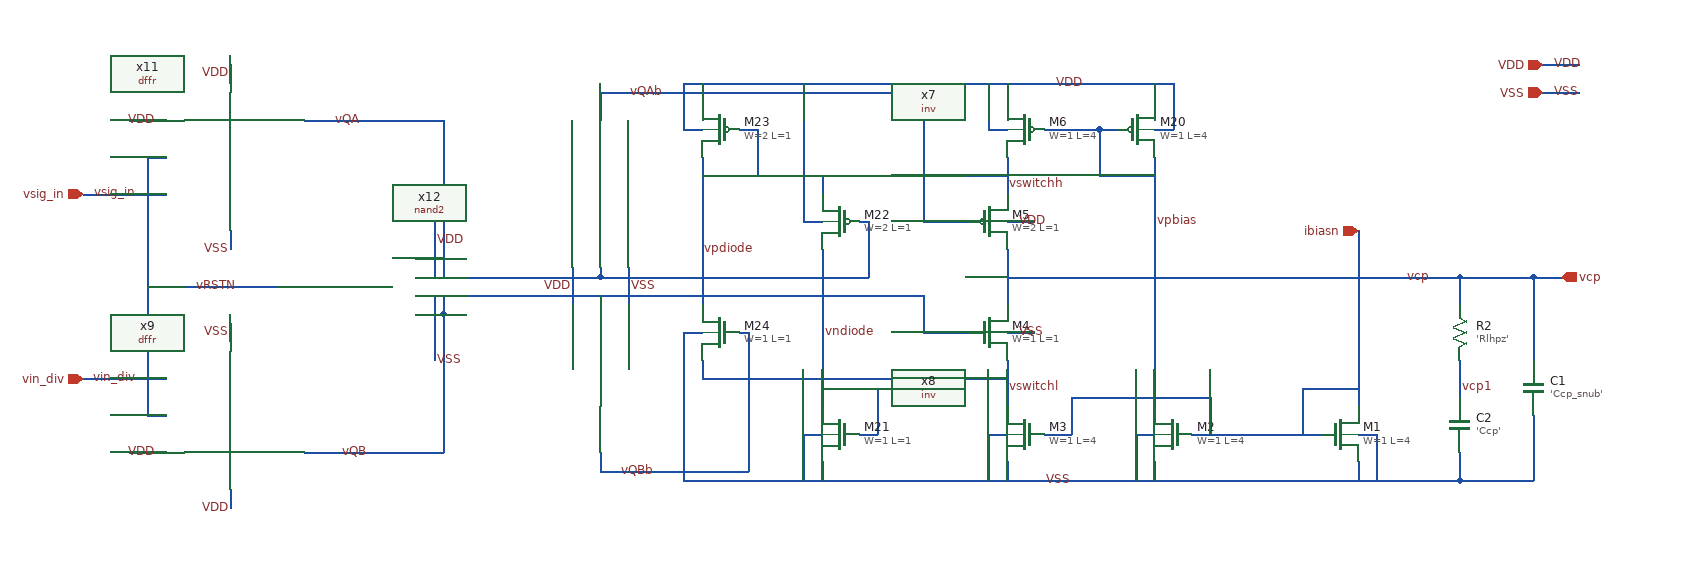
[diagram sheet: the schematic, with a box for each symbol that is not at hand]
v {xschem version=2.9.9 file_version=1.2 }
G {}
K {}
V {}
S {}
E {}
N 160 -260 250 -260 { lab=vin_div}
N 160 -460 250 -460 { lab=vsig_in}
N 1320 -170 1320 -150 { lab=VSS}
N 1300 -200 1320 -200 { lab=VSS}
N 1300 -200 1300 -150 { lab=VSS}
N 1320 -530 1340 -530 { lab=VDD}
N 1320 -580 1320 -560 { lab=VDD}
N 1340 -580 1340 -530 { lab=VDD}
N 1360 -200 1430 -200 { lab=ibiasn}
N 1260 -530 1260 -480 { lab=vpbias}
N 1260 -480 1320 -480 { lab=vpbias}
N 1260 -530 1280 -530 { lab=vpbias}
N 1320 -500 1320 -230 { lab=vpbias}
N 1540 -170 1540 -150 { lab=VSS}
N 1540 -200 1560 -200 { lab=VSS}
N 1560 -200 1560 -150 { lab=VSS}
N 1200 -530 1260 -530 { lab=vpbias}
N 1140 -530 1160 -530 { lab=VDD}
N 1140 -580 1140 -530 { lab=VDD}
N 1160 -580 1160 -560 { lab=VDD}
N 1160 -170 1160 -150 { lab=VSS}
N 1140 -200 1160 -200 { lab=VSS}
N 1140 -200 1140 -150 { lab=VSS}
N 1380 -240 1380 -200 { lab=ibiasn}
N 1230 -240 1380 -240 { lab=ibiasn}
N 1230 -240 1230 -200 { lab=ibiasn}
N 1200 -200 1230 -200 { lab=ibiasn}
N 1160 -500 1160 -460 { lab=vswitchh}
N 1160 -400 1160 -340 { lab=vcp}
N 1160 -280 1160 -230 { lab=vswitchl}
N 1160 -310 1190 -310 { lab=VSS}
N 1160 -430 1190 -430 { lab=VDD}
N 1540 -420 1540 -230 { lab=ibiasn}
N 1480 -250 1540 -250 { lab=ibiasn}
N 1160 -370 1580 -370 { lab=vcp}
N 940 -430 960 -430 { lab=VDD}
N 1000 -200 1020 -200 { lab=vndiode}
N 1020 -250 1020 -200 { lab=vndiode}
N 960 -250 1020 -250 { lab=vndiode}
N 830 -280 830 -260 { lab=vswitchl}
N 810 -310 830 -310 { lab=VSS}
N 810 -530 830 -530 { lab=VDD}
N 810 -580 810 -530 { lab=VDD}
N 830 -580 830 -560 { lab=VDD}
N 940 -200 960 -200 { lab=VSS}
N 960 -170 960 -150 { lab=VSS}
N 940 -200 940 -150 { lab=VSS}
N 870 -530 890 -530 { lab=vpdiode}
N 890 -530 890 -480 { lab=vpdiode}
N 830 -480 890 -480 { lab=vpdiode}
N 960 -480 1160 -480 { lab=vswitchh}
N 830 -260 1160 -260 { lab=vswitchl}
N 1100 -430 1120 -430 { lab=vQAb}
N 1000 -430 1010 -430 { lab=vQA}
N 1100 -310 1120 -310 { lab=vQB}
N 870 -310 880 -310 { lab=vQBb}
N 1070 -430 1100 -430 { lab=vQAb}
N 1070 -350 1070 -310 { lab=vQB}
N 1070 -310 1100 -310 { lab=vQB}
N 960 -480 960 -460 { lab=vswitchh}
N 960 -400 960 -230 { lab=vndiode}
N 940 -580 940 -430 { lab=VDD}
N 810 -310 810 -150 { lab=VSS}
N 830 -500 830 -340 { lab=vpdiode}
N 400 -540 550 -540 { lab=vQA}
N 400 -180 550 -180 { lab=vQB}
N 230 -360 370 -360 { lab=vRSTN}
N 720 -570 720 -540 { lab=vQAb}
N 720 -180 720 -160 { lab=vQBb}
N 720 -380 720 -370 { lab=vQA}
N 720 -350 720 -340 { lab=vQB}
N 550 -540 550 -370 { lab=vQA}
N 550 -370 720 -370 { lab=vQA}
N 720 -570 1070 -570 { lab=vQAb}
N 1070 -570 1070 -430 { lab=vQAb}
N 720 -370 1010 -370 { lab=vQA}
N 1010 -430 1010 -370 { lab=vQA}
N 550 -350 550 -330 { lab=vQB}
N 550 -350 1070 -350 { lab=vQB}
N 720 -160 880 -160 { lab=vQBb}
N 880 -310 880 -160 { lab=vQBb}
N 230 -220 250 -220 { lab=vRSTN}
N 230 -500 230 -220 { lab=vRSTN}
N 230 -500 250 -500 { lab=vRSTN}
N 210 -540 250 -540 { lab=VDD}
N 210 -180 250 -180 { lab=VDD}
N 550 -330 550 -180 { lab=vQB}
N 1430 -200 1500 -200 { lab=ibiasn}
N 1480 -250 1480 -200 { lab=ibiasn}
N 1650 -370 1650 -340 { lab=vcp}
N 1650 -180 1650 -150 { lab=VSS}
N 1650 -280 1650 -240 { lab=vcp1}
N 1580 -370 1650 -370 { lab=vcp}
N 810 -150 1650 -150 { lab=VSS}
N 1650 -370 1730 -370 { lab=vcp}
N 1730 -370 1730 -280 { lab=vcp}
N 1730 -220 1730 -150 { lab=VSS}
N 1650 -150 1730 -150 { lab=VSS}
N 1740 -570 1780 -570 { lab=VSS}
N 1740 -600 1780 -600 { lab=VDD}
N 1730 -370 1760 -370 { lab=vcp}
N 810 -580 1340 -580 { lab=VDD}
N 690 -380 690 -340 { lab=VDD}
N 750 -380 750 -340 { lab=VSS}
N 320 -420 320 -400 { lab=VSS}
N 320 -600 320 -580 { lab=VDD}
N 320 -320 320 -300 { lab=VSS}
N 320 -140 320 -120 { lab=VDD}
N 540 -310 540 -280 { lab=#net1}
N 540 -430 540 -400 { lab=VDD}
N 520 -390 550 -390 {}
N 520 -330 550 -330 {}
N 520 -370 540 -370 {}
N 540 -400 540 -370 {}
N 540 -350 540 -310 {}
N 520 -350 540 -350 {}
C {devices/title.sym} 160 -30 0 0 {name=l1 author="Nikhil Poole"}
C {devices/lab_wire.sym} 220 -460 0 0 {name=l2 sig_type=std_logic lab=vsig_in}
C {devices/lab_wire.sym} 220 -260 0 0 {name=l3 sig_type=std_logic lab=vin_div}
C {devices/lab_wire.sym} 1320 -430 0 1 {name=l6 sig_type=std_logic lab=vpbias}
C {sky130_fd_pr/nfet_01v8.sym} 1520 -200 0 0 {name=M1
L=4
W=1
nf=1 
mult=10
ad="'int((nf+1)/2) * W/nf * 0.29'" 
pd="'2*int((nf+1)/2) * (W/nf + 0.29)'"
as="'int((nf+2)/2) * W/nf * 0.29'" 
ps="'2*int((nf+2)/2) * (W/nf + 0.29)'"
nrd="'0.29 / W'" nrs="'0.29 / W'"
sa=0 sb=0 sd=0
model=nfet_01v8
spiceprefix=X
}
C {sky130_fd_pr/nfet_01v8.sym} 1340 -200 0 1 {name=M2
L=4
W=1
nf=1 
mult=1
ad="'int((nf+1)/2) * W/nf * 0.29'" 
pd="'2*int((nf+1)/2) * (W/nf + 0.29)'"
as="'int((nf+2)/2) * W/nf * 0.29'" 
ps="'2*int((nf+2)/2) * (W/nf + 0.29)'"
nrd="'0.29 / W'" nrs="'0.29 / W'"
sa=0 sb=0 sd=0
model=nfet_01v8
spiceprefix=X
}
C {sky130_fd_pr/nfet_01v8.sym} 1180 -200 0 1 {name=M3
L=4
W=1
nf=1 
mult=1
ad="'int((nf+1)/2) * W/nf * 0.29'" 
pd="'2*int((nf+1)/2) * (W/nf + 0.29)'"
as="'int((nf+2)/2) * W/nf * 0.29'" 
ps="'2*int((nf+2)/2) * (W/nf + 0.29)'"
nrd="'0.29 / W'" nrs="'0.29 / W'"
sa=0 sb=0 sd=0
model=nfet_01v8
spiceprefix=X
}
C {sky130_fd_pr/nfet_01v8_lvt.sym} 1140 -310 0 0 {name=M4
L=1
W=1
nf=1
mult=1
ad="'int((nf+1)/2) * W/nf * 0.29'" 
pd="'2*int((nf+1)/2) * (W/nf + 0.29)'"
as="'int((nf+2)/2) * W/nf * 0.29'" 
ps="'2*int((nf+2)/2) * (W/nf + 0.29)'"
nrd="'0.29 / W'" nrs="'0.29 / W'"
sa=0 sb=0 sd=0
model=nfet_01v8_lvt
spiceprefix=X
}
C {sky130_fd_pr/pfet_01v8_lvt.sym} 1140 -430 0 0 {name=M5
L=1
W=2
nf=1
mult=1
ad="'int((nf+1)/2) * W/nf * 0.29'" 
pd="'2*int((nf+1)/2) * (W/nf + 0.29)'"
as="'int((nf+2)/2) * W/nf * 0.29'" 
ps="'2*int((nf+2)/2) * (W/nf + 0.29)'"
nrd="'0.29 / W'" nrs="'0.29 / W'"
sa=0 sb=0 sd=0
model=pfet_01v8_lvt
spiceprefix=X
}
C {sky130_fd_pr/pfet_01v8.sym} 1180 -530 0 1 {name=M6
L=4
W=1
nf=1
mult=8
ad="'int((nf+1)/2) * W/nf * 0.29'" 
pd="'2*int((nf+1)/2) * (W/nf + 0.29)'"
as="'int((nf+2)/2) * W/nf * 0.29'" 
ps="'2*int((nf+2)/2) * (W/nf + 0.29)'"
nrd="'0.29 / W'" nrs="'0.29 / W'"
sa=0 sb=0 sd=0
model=pfet_01v8
spiceprefix=X
}
C {sky130_fd_pr/pfet_01v8.sym} 1300 -530 0 0 {name=M20
L=4
W=1
nf=1
mult=8
ad="'int((nf+1)/2) * W/nf * 0.29'" 
pd="'2*int((nf+1)/2) * (W/nf + 0.29)'"
as="'int((nf+2)/2) * W/nf * 0.29'" 
ps="'2*int((nf+2)/2) * (W/nf + 0.29)'"
nrd="'0.29 / W'" nrs="'0.29 / W'"
sa=0 sb=0 sd=0
model=pfet_01v8
spiceprefix=X
}
C {devices/capa.sym} 1650 -210 0 0 {name=C2
m=1
value='Ccp'
footprint=1206
device="ceramic capacitor"}
C {devices/lab_wire.sym} 470 -180 0 0 {name=l37 sig_type=std_logic lab=vQB}
C {devices/lab_wire.sym} 1160 -470 0 1 {name=l38 sig_type=std_logic lab=vswitchh}
C {devices/lab_wire.sym} 1160 -250 0 1 {name=l39 sig_type=std_logic lab=vswitchl}
C {sky130_fd_pr/nfet_01v8.sym} 980 -200 0 1 {name=M21
L=1
W=1
nf=1 
mult=1
ad="'int((nf+1)/2) * W/nf * 0.29'" 
pd="'2*int((nf+1)/2) * (W/nf + 0.29)'"
as="'int((nf+2)/2) * W/nf * 0.29'" 
ps="'2*int((nf+2)/2) * (W/nf + 0.29)'"
nrd="'0.29 / W'" nrs="'0.29 / W'"
sa=0 sb=0 sd=0
model=nfet_01v8
spiceprefix=X
}
C {sky130_fd_pr/pfet_01v8.sym} 980 -430 0 1 {name=M22
L=1
W=2
nf=1
mult=1
ad="'int((nf+1)/2) * W/nf * 0.29'" 
pd="'2*int((nf+1)/2) * (W/nf + 0.29)'"
as="'int((nf+2)/2) * W/nf * 0.29'" 
ps="'2*int((nf+2)/2) * (W/nf + 0.29)'"
nrd="'0.29 / W'" nrs="'0.29 / W'"
sa=0 sb=0 sd=0
model=pfet_01v8
spiceprefix=X
}
C {devices/lab_wire.sym} 430 -540 0 1 {name=l40 sig_type=std_logic lab=vQA}
C {sky130_fd_pr/pfet_01v8.sym} 850 -530 0 1 {name=M23
L=1
W=2
nf=1
mult=1
ad="'int((nf+1)/2) * W/nf * 0.29'" 
pd="'2*int((nf+1)/2) * (W/nf + 0.29)'"
as="'int((nf+2)/2) * W/nf * 0.29'" 
ps="'2*int((nf+2)/2) * (W/nf + 0.29)'"
nrd="'0.29 / W'" nrs="'0.29 / W'"
sa=0 sb=0 sd=0
model=pfet_01v8
spiceprefix=X
}
C {sky130_fd_pr/nfet_01v8.sym} 850 -310 0 1 {name=M24
L=1
W=1
nf=1 
mult=1
ad="'int((nf+1)/2) * W/nf * 0.29'" 
pd="'2*int((nf+1)/2) * (W/nf + 0.29)'"
as="'int((nf+2)/2) * W/nf * 0.29'" 
ps="'2*int((nf+2)/2) * (W/nf + 0.29)'"
nrd="'0.29 / W'" nrs="'0.29 / W'"
sa=0 sb=0 sd=0
model=nfet_01v8
spiceprefix=X
}
C {devices/lab_wire.sym} 780 -160 0 0 {name=l41 sig_type=std_logic lab=vQBb}
C {devices/lab_wire.sym} 1590 -370 0 1 {name=l44 sig_type=std_logic lab=vcp}
C {devices/lab_wire.sym} 280 -360 0 1 {name=l49 sig_type=std_logic lab=vRSTN}
C {/home/users/nhpoole/ee272b/ee272b_mixed_signal_mmwave_accelerator/designs/inv.sym} 720 -430 3 0 {name=x7 M=1}
C {/home/users/nhpoole/ee272b/ee272b_mixed_signal_mmwave_accelerator/designs/inv.sym} 720 -290 3 1 {name=x8 M=1}
C {devices/lab_wire.sym} 790 -570 0 0 {name=l50 sig_type=std_logic lab=vQAb}
C {/home/users/nhpoole/ee272b/ee272b_mixed_signal_mmwave_accelerator/designs/dffr.sym} 320 -220 2 1 {name=x9 M=1}
C {/home/users/nhpoole/ee272b/ee272b_mixed_signal_mmwave_accelerator/designs/dffr.sym} 320 -500 0 0 {name=x11 M=1}
C {/home/users/nhpoole/ee272b/ee272b_mixed_signal_mmwave_accelerator/designs/nand2.sym} 450 -360 0 1 {name=x12 M=1}
C {devices/res.sym} 1650 -310 0 0 {name=R2
value='Rlhpz'
footprint=1206
device=resistor
m=1}
C {devices/noconn.sym} 400 -260 0 1 {name=l11}
C {devices/noconn.sym} 400 -460 0 1 {name=l13}
C {devices/lab_wire.sym} 1650 -250 0 1 {name=l4 sig_type=std_logic lab=vcp1}
C {devices/capa.sym} 1730 -250 0 0 {name=C1
m=1
value='Ccp_snub'
footprint=1206
device="ceramic capacitor"}
C {devices/lab_wire.sym} 1210 -580 0 1 {name=l8 sig_type=std_logic lab=VDD}
C {devices/lab_wire.sym} 1200 -150 0 1 {name=l9 sig_type=std_logic lab=VSS}
C {devices/lab_wire.sym} 1170 -310 0 1 {name=l7 sig_type=std_logic lab=VSS}
C {devices/lab_wire.sym} 1170 -430 0 1 {name=l10 sig_type=std_logic lab=VDD}
C {devices/lab_wire.sym} 240 -540 0 0 {name=l12 sig_type=std_logic lab=VDD}
C {devices/lab_wire.sym} 240 -180 0 0 {name=l14 sig_type=std_logic lab=VDD}
C {devices/ipin.sym} 1740 -600 0 0 {name=p1 lab=VDD}
C {devices/ipin.sym} 1740 -570 0 0 {name=p2 lab=VSS}
C {devices/lab_wire.sym} 1750 -570 0 1 {name=l20 sig_type=std_logic lab=VSS}
C {devices/lab_wire.sym} 1750 -600 0 1 {name=l21 sig_type=std_logic lab=VDD}
C {devices/ipin.sym} 160 -260 0 0 {name=p3 lab=vin_div}
C {devices/ipin.sym} 160 -460 0 0 {name=p4 lab=vsig_in}
C {devices/opin.sym} 1760 -370 0 0 {name=p5 lab=vcp}
C {devices/ipin.sym} 1540 -420 1 0 {name=p6 lab=ibiasn}
C {devices/lab_wire.sym} 750 -360 0 1 {name=l5 sig_type=std_logic lab=VSS}
C {devices/lab_wire.sym} 690 -360 0 0 {name=l15 sig_type=std_logic lab=VDD}
C {devices/lab_wire.sym} 960 -310 0 1 {name=l16 sig_type=std_logic lab=vndiode}
C {devices/lab_wire.sym} 830 -400 0 1 {name=l17 sig_type=std_logic lab=vpdiode}
C {devices/lab_wire.sym} 320 -590 0 0 {name=l18 sig_type=std_logic lab=VDD}
C {devices/lab_wire.sym} 320 -400 0 0 {name=l19 sig_type=std_logic lab=VSS}
C {devices/lab_wire.sym} 320 -310 0 0 {name=l22 sig_type=std_logic lab=VSS}
C {devices/lab_wire.sym} 320 -120 0 0 {name=l23 sig_type=std_logic lab=VDD}
C {devices/lab_wire.sym} 540 -410 0 1 {name=l24 sig_type=std_logic lab=VDD}
C {devices/lab_wire.sym} 540 -280 0 1 {name=l25 sig_type=std_logic lab=VSS}
